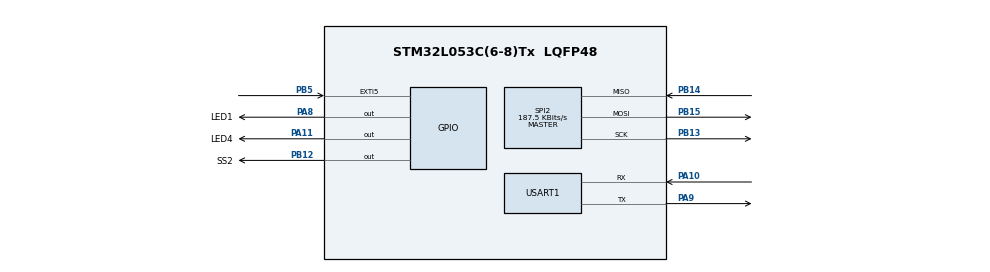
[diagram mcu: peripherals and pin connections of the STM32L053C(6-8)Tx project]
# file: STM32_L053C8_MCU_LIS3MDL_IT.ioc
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Dma.Request0=SPI2_RX
Dma.Request1=SPI2_TX
Dma.SPI2_RX.0.Direction=DMA_PERIPH_TO_MEMORY
Dma.SPI2_RX.0.Instance=DMA1_Channel4
Dma.SPI2_RX.0.MemDataAlignment=DMA_MDATAALIGN_BYTE
Dma.SPI2_RX.0.MemInc=DMA_MINC_ENABLE
Dma.SPI2_RX.0.Mode=DMA_NORMAL
Dma.SPI2_RX.0.PeriphDataAlignment=DMA_PDATAALIGN_BYTE
Dma.SPI2_RX.0.PeriphInc=DMA_PINC_DISABLE
Dma.SPI2_RX.0.Priority=DMA_PRIORITY_LOW
Dma.SPI2_TX.1.Direction=DMA_MEMORY_TO_PERIPH
Dma.SPI2_TX.1.Instance=DMA1_Channel5
Dma.SPI2_TX.1.MemDataAlignment=DMA_MDATAALIGN_BYTE
Dma.SPI2_TX.1.MemInc=DMA_MINC_ENABLE
Dma.SPI2_TX.1.Mode=DMA_NORMAL
Dma.SPI2_TX.1.PeriphDataAlignment=DMA_PDATAALIGN_BYTE
Dma.SPI2_TX.1.PeriphInc=DMA_PINC_DISABLE
Dma.SPI2_TX.1.Priority=DMA_PRIORITY_LOW
Mcu.Family=STM32L0
Mcu.Name=STM32L053C(6-8)Tx
Mcu.Package=LQFP48
NVIC.DMA1_Channel4_5_6_7_IRQn=true\:0\:0\:false\:false\:true\:false\:true\:true
NVIC.EXTI4_15_IRQn=true\:0\:0\:false\:false\:true\:true\:true\:true
NVIC.SPI2_IRQn=true\:0\:0\:true\:false\:true\:true\:true\:true
NVIC.TIM6_DAC_IRQn=true\:0\:0\:false\:false\:true\:true\:true\:true
NVIC.USART1_IRQn=true\:0\:0\:false\:false\:true\:true\:true\:true
PA10.Mode=Asynchronous
PA10.Signal=USART1_RX
PA11.GPIO_Label=LED4
PA11.Signal=GPIO_Output
PA13.Mode=Serial_Wire
PA13.Signal=SYS_SWDIO
PA14.Mode=Serial_Wire
PA14.Signal=SYS_SWCLK
PA8.GPIO_Label=LED1
PA8.Signal=GPIO_Output
PA9.Mode=Asynchronous
PA9.Signal=USART1_TX
PB12.GPIO_Label=SS2
PB12.Signal=GPIO_Output
PB13.GPIO_PuPd=GPIO_NOPULL
PB13.Mode=Full_Duplex_Master
PB13.Signal=SPI2_SCK
PB14.GPIO_PuPd=GPIO_NOPULL
PB14.Mode=Full_Duplex_Master
PB14.Signal=SPI2_MISO
PB15.GPIO_PuPd=GPIO_NOPULL
PB15.Mode=Full_Duplex_Master
PB15.Signal=SPI2_MOSI
PB5.GPIO_ModeDefaultEXTI=GPIO_MODE_IT_RISING
PB5.Signal=GPXTI5
PH0-OSC_IN.Mode=HSE-External-Oscillator
PH0-OSC_IN.Signal=RCC_OSC_IN
PH1-OSC_OUT.Mode=HSE-External-Oscillator
PH1-OSC_OUT.Signal=RCC_OSC_OUT
ProjectManager.HeapSize=0x200
ProjectManager.StackSize=0x400
ProjectManager.TargetToolchain=STM32CubeIDE
RCC.AHBFreq_Value=24000000
RCC.APB1CLKDivider=RCC_HCLK_DIV2
RCC.APB1Freq_Value=12000000
RCC.APB1TimFreq_Value=24000000
RCC.APB2Freq_Value=24000000
RCC.APB2TimFreq_Value=24000000
RCC.HCLKFreq_Value=24000000
RCC.HSE_VALUE=8000000
RCC.HSI16_VALUE=16000000
RCC.HSI48_VALUE=48000000
RCC.HSI_VALUE=16000000
RCC.LSE_VALUE=32768
RCC.MSI_VALUE=2097000
RCC.SYSCLKFreq_VALUE=24000000
RCC.SYSCLKSource=RCC_SYSCLKSOURCE_PLLCLK
RCC.VCOOutputFreq_Value=48000000
SPI2.BaudRatePrescaler=SPI_BAUDRATEPRESCALER_64
SPI2.CLKPhase=SPI_PHASE_2EDGE
SPI2.CLKPolarity=SPI_POLARITY_HIGH
SPI2.CalculateBaudRate=187.5 KBits/s
SPI2.Direction=SPI_DIRECTION_2LINES
SPI2.Mode=SPI_MODE_MASTER
SPI2.VirtualType=VM_MASTER
TIM6.AutoReloadPreload=TIM_AUTORELOAD_PRELOAD_ENABLE
TIM6.Period=99
TIM6.Prescaler=32
USART1.VirtualMode-Asynchronous=VM_ASYNC
VP_SYS_V_PVD_IN.Mode=Mode_PVD_Int
VP_TIM6_VS_ClockSourceINT.Mode=Enable_Timer
board=custom

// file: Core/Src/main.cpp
/* USER CODE BEGIN Header */
/**
  ******************************************************************************
  * @file           : main.cpp
  * @brief          : Main program body
  ******************************************************************************
  * @attention
  *
  * Copyright (c) 2024 STMicroelectronics.
  * All rights reserved.
  *
  * This software is licensed under terms that can be found in the LICENSE file
  * in the root directory of this software component.
  * If no LICENSE file comes with this software, it is provided AS-IS.
  *
  ******************************************************************************
  */
/* USER CODE END Header */
#include "main.h"
/* USER CODE BEGIN Includes */
#include <string.h>
#include "lis3mdl.hpp"
#include "magnetometerRawData.hpp"
#include "helpers.h"
/* USER CODE END Includes */

SPI_HandleTypeDef hspi2;
DMA_HandleTypeDef hdma_spi2_rx;
DMA_HandleTypeDef hdma_spi2_tx;

TIM_HandleTypeDef htim6;

/* USER CODE BEGIN PV */
UART_HandleTypeDef huart1;

volatile int data_ready = 0;
volatile int config_ready = 0;
/* USER CODE END PV */

void SystemClock_Config(void);
static void MX_GPIO_Init(void);
static void MX_DMA_Init(void);
static void MX_SPI2_Init(void);
static void MX_TIM6_Init(void);
/* USER CODE BEGIN PFP */
static void MX_USART1_UART_Init(void);
/* USER CODE END PFP */

/* USER CODE BEGIN 0 */
void HAL_GPIO_EXTI_Callback(uint16_t GPIO_Pin)
{
	data_ready = 1;
}

void HAL_UART_RxCpltCallback(UART_HandleTypeDef *huart)
{
	config_ready = 1;
}
/* USER CODE END 0 */

int main(void)
{

  /* MCU Configuration--------------------------------------------------------*/

  /* Reset of all peripherals, Initializes the Flash interface and the Systick. */
  HAL_Init();

  /* Configure the system clock */
  SystemClock_Config();

  /* Initialize all configured peripherals */
  MX_GPIO_Init();
  MX_DMA_Init();
  MX_SPI2_Init();
  MX_TIM6_Init();
  MX_USART1_UART_Init();
  /* USER CODE BEGIN 2 */

  MagnetometerRawData magRawData;
  uint8_t config_data[4];

  // Non blocking mode on by default
  BlockingMode non_blocking = BlockingMode::NONBLOCKING;

  ConfigHandler config_handler(&hspi2);
  /* USER CODE END 2 */

  /* Infinite loop */
  while (1)
  {

	  if (non_blocking == BlockingMode::NONBLOCKING) {
		  // Non-blocking mode based on DRDY pin interrupt
		  if (data_ready) {
			  data_ready = 0;

			  LIS3MDL_WriteRegister(CTRL_REG3, ZERO_VALUE, hspi2);
			  magRawData.get_axis_data(hspi2);

		  	  float calib[3];
		  	  calibrate(magRawData, calib);

			  int heading;
		 	  calculate_heading(calib, &heading, magRawData.get_z());

	  		  handle_leds(heading);
	 		  send_heading_uart(heading, huart1);
	  	  }
	  }
	  else {
		  // Blocking mode based on polling method
		  LIS3MDL_WriteRegister(CTRL_REG3, ZERO_VALUE, hspi2);

		  HAL_Delay(100);
		  uint8_t statusReg = LIS3MDL_ReadRegister(STATUS_REG, hspi2);
		  if (((statusReg & (1 << 2)) != 0) && ((statusReg & (1 << 6)) != 0)) {
			  magRawData.get_axis_data(hspi2);

		  	  float calib[3];
		  	  calibrate(magRawData, calib);

		  	  int heading;
		      calculate_heading(calib, &heading, magRawData.get_z());

		  	  handle_leds(heading);
		  	  send_heading_uart(heading, huart1);
		  }
	  }

	  HAL_UART_Receive_IT(&huart1, config_data, 4);
	  if (config_ready) {
		  config_ready = 0;

		  handle_config_callback(huart1, config_handler, config_data, hspi2);

		  // Set blocking mode
		  non_blocking = config_handler.get_blocking_mode();
	  }
  }
}

void SystemClock_Config(void)
{
  RCC_OscInitTypeDef RCC_OscInitStruct = {0};
  RCC_ClkInitTypeDef RCC_ClkInitStruct = {0};
  RCC_PeriphCLKInitTypeDef PeriphClkInit = {0};

  /** Configure the main internal regulator output voltage
  */
  __HAL_PWR_VOLTAGESCALING_CONFIG(PWR_REGULATOR_VOLTAGE_SCALE1);

  /** Initializes the RCC Oscillators according to the specified parameters
  * in the RCC_OscInitTypeDef structure.
  */
  RCC_OscInitStruct.OscillatorType = RCC_OSCILLATORTYPE_HSI;
  RCC_OscInitStruct.HSIState = RCC_HSI_ON;
  RCC_OscInitStruct.HSICalibrationValue = RCC_HSICALIBRATION_DEFAULT;
  RCC_OscInitStruct.PLL.PLLState = RCC_PLL_ON;
  RCC_OscInitStruct.PLL.PLLSource = RCC_PLLSOURCE_HSI;
  RCC_OscInitStruct.PLL.PLLMUL = RCC_PLLMUL_4;
  RCC_OscInitStruct.PLL.PLLDIV = RCC_PLLDIV_2;
  if (HAL_RCC_OscConfig(&RCC_OscInitStruct) != HAL_OK)
  {
    Error_Handler();
  }

  /** Initializes the CPU, AHB and APB buses clocks
  */
  RCC_ClkInitStruct.ClockType = RCC_CLOCKTYPE_HCLK|RCC_CLOCKTYPE_SYSCLK
                              |RCC_CLOCKTYPE_PCLK1|RCC_CLOCKTYPE_PCLK2;
  RCC_ClkInitStruct.SYSCLKSource = RCC_SYSCLKSOURCE_PLLCLK;
  RCC_ClkInitStruct.AHBCLKDivider = RCC_SYSCLK_DIV1;
  RCC_ClkInitStruct.APB1CLKDivider = RCC_HCLK_DIV1;
  RCC_ClkInitStruct.APB2CLKDivider = RCC_HCLK_DIV1;

  if (HAL_RCC_ClockConfig(&RCC_ClkInitStruct, FLASH_LATENCY_1) != HAL_OK)
  {
    Error_Handler();
  }
  PeriphClkInit.PeriphClockSelection = RCC_PERIPHCLK_USART1;
  PeriphClkInit.Usart1ClockSelection = RCC_USART2CLKSOURCE_PCLK1;
  if (HAL_RCCEx_PeriphCLKConfig(&PeriphClkInit) != HAL_OK)
  {
    Error_Handler();
  }
}

static void MX_SPI2_Init(void)
{

  /* SPI2 parameter configuration*/
  hspi2.Instance = SPI2;
  hspi2.Init.Mode = SPI_MODE_MASTER;
  hspi2.Init.Direction = SPI_DIRECTION_2LINES;
  hspi2.Init.DataSize = SPI_DATASIZE_8BIT;
  hspi2.Init.CLKPolarity = SPI_POLARITY_LOW;
  hspi2.Init.CLKPhase = SPI_PHASE_1EDGE;
  hspi2.Init.NSS = SPI_NSS_SOFT;
  hspi2.Init.BaudRatePrescaler = SPI_BAUDRATEPRESCALER_16;
  //Set polarity to CPOL = 0 and CPHA = 0
  hspi2.Init.FirstBit = SPI_FIRSTBIT_MSB;
  hspi2.Init.TIMode = SPI_TIMODE_DISABLE;

  hspi2.Init.CRCCalculation = SPI_CRCCALCULATION_DISABLE;
  hspi2.Init.CRCPolynomial = 7;
  if (HAL_SPI_Init(&hspi2) != HAL_OK)
  {
    Error_Handler();
  }

}

static void MX_TIM6_Init(void)
{

  TIM_MasterConfigTypeDef sMasterConfig = {0};

  htim6.Instance = TIM6;
  htim6.Init.Prescaler = 32;
  htim6.Init.CounterMode = TIM_COUNTERMODE_UP;
  htim6.Init.Period = 99;
  htim6.Init.AutoReloadPreload = TIM_AUTORELOAD_PRELOAD_ENABLE;
  if (HAL_TIM_Base_Init(&htim6) != HAL_OK)
  {
    Error_Handler();
  }
  sMasterConfig.MasterOutputTrigger = TIM_TRGO_RESET;
  sMasterConfig.MasterSlaveMode = TIM_MASTERSLAVEMODE_DISABLE;
  if (HAL_TIMEx_MasterConfigSynchronization(&htim6, &sMasterConfig) != HAL_OK)
  {
    Error_Handler();
  }

}

static void MX_DMA_Init(void)
{

  /* DMA controller clock enable */
  __HAL_RCC_DMA1_CLK_ENABLE();

  /* DMA interrupt init */
  /* DMA1_Channel4_5_6_7_IRQn interrupt configuration */
  HAL_NVIC_SetPriority(DMA1_Channel4_5_6_7_IRQn, 0, 0);
  HAL_NVIC_EnableIRQ(DMA1_Channel4_5_6_7_IRQn);

}

static void MX_GPIO_Init(void)
{
  GPIO_InitTypeDef GPIO_InitStruct = {0};

  /* GPIO Ports Clock Enable */
  __HAL_RCC_GPIOB_CLK_ENABLE();
  __HAL_RCC_GPIOA_CLK_ENABLE();

  /*Configure GPIO pin Output Level */
  HAL_GPIO_WritePin(SS2_GPIO_Port, SS2_Pin, GPIO_PIN_RESET);

  /*Configure GPIO pin : SS2_Pin */
  GPIO_InitStruct.Pin = SS2_Pin;
  GPIO_InitStruct.Mode = GPIO_MODE_OUTPUT_PP;
  GPIO_InitStruct.Pull = GPIO_NOPULL;
  GPIO_InitStruct.Speed = GPIO_SPEED_FREQ_LOW;
  HAL_GPIO_Init(SS2_GPIO_Port, &GPIO_InitStruct);

  GPIO_InitStruct.Pin = GPIO_PIN_4;
  GPIO_InitStruct.Mode = GPIO_MODE_OUTPUT_PP;
  GPIO_InitStruct.Pull = GPIO_NOPULL;
  GPIO_InitStruct.Speed = GPIO_SPEED_FREQ_LOW;
  HAL_GPIO_Init(GPIOB, &GPIO_InitStruct);

  GPIO_InitStruct.Pin = GPIO_PIN_5;
  GPIO_InitStruct.Mode = GPIO_MODE_OUTPUT_PP;
  GPIO_InitStruct.Pull = GPIO_NOPULL;
  GPIO_InitStruct.Speed = GPIO_SPEED_FREQ_LOW;
  HAL_GPIO_Init(GPIOA, &GPIO_InitStruct);

  GPIO_InitStruct.Pin = GPIO_PIN_5;
  GPIO_InitStruct.Mode = GPIO_MODE_IT_RISING;
  GPIO_InitStruct.Pull = GPIO_NOPULL;
  HAL_GPIO_Init(GPIOB, &GPIO_InitStruct);

  /* EXTI interrupt init*/
  HAL_NVIC_SetPriority(EXTI4_15_IRQn, 0, 0);
  HAL_NVIC_EnableIRQ(EXTI4_15_IRQn);

}

/* USER CODE BEGIN 4 */
/**
  * @brief USART1 Initialization Function
  * @param None
  * @retval None
  */
static void MX_USART1_UART_Init(void)
{

  /* USER CODE BEGIN USART1_Init 0 */

  /* USER CODE END USART1_Init 0 */

  /* USER CODE BEGIN USART1_Init 1 */

  /* USER CODE END USART1_Init 1 */
  huart1.Instance = USART1;
  huart1.Init.BaudRate = 115200;
  huart1.Init.WordLength = UART_WORDLENGTH_8B;
  huart1.Init.StopBits = UART_STOPBITS_1;
  huart1.Init.Parity = UART_PARITY_NONE;
  huart1.Init.Mode = UART_MODE_TX_RX;
  huart1.Init.HwFlowCtl = UART_HWCONTROL_NONE;
  huart1.Init.OverSampling = UART_OVERSAMPLING_16;
  huart1.Init.OneBitSampling = UART_ONE_BIT_SAMPLE_DISABLE;
  huart1.AdvancedInit.AdvFeatureInit = UART_ADVFEATURE_NO_INIT;
  if (HAL_UART_Init(&huart1) != HAL_OK)
  {
    Error_Handler();
  }
  /* USER CODE BEGIN USART1_Init 2 */

  /* USER CODE END USART1_Init 2 */

}
/* USER CODE END 4 */

void Error_Handler(void)
{
  __disable_irq();
  while (1)
  {
  }
}
